VERSION 5.7 ;
  NOWIREEXTENSIONATPIN ON ;
  DIVIDERCHAR "/" ;
  BUSBITCHARS "[]" ;
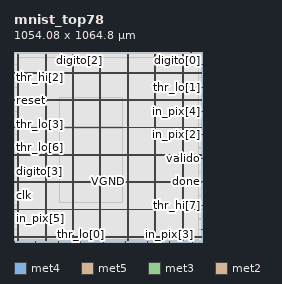
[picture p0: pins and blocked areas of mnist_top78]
MACRO mnist_top78
  CLASS BLOCK ;
  FOREIGN mnist_top78 ;
  ORIGIN 0.000 0.000 ;
  SIZE 1054.075 BY 1064.795 ;
  PIN VGND
    DIRECTION INOUT ;
    USE GROUND ;
    PORT
      LAYER met4 ;
        RECT 24.340 10.640 25.940 1052.880 ;
    END
    PORT
      LAYER met4 ;
        RECT 177.940 10.640 179.540 1052.880 ;
    END
    PORT
      LAYER met4 ;
        RECT 331.540 10.640 333.140 1052.880 ;
    END
    PORT
      LAYER met4 ;
        RECT 485.140 10.640 486.740 1052.880 ;
    END
    PORT
      LAYER met4 ;
        RECT 638.740 10.640 640.340 1052.880 ;
    END
    PORT
      LAYER met4 ;
        RECT 792.340 10.640 793.940 1052.880 ;
    END
    PORT
      LAYER met4 ;
        RECT 945.940 10.640 947.540 1052.880 ;
    END
    PORT
      LAYER met5 ;
        RECT 5.280 30.030 1048.580 31.630 ;
    END
    PORT
      LAYER met5 ;
        RECT 5.280 183.210 1048.580 184.810 ;
    END
    PORT
      LAYER met5 ;
        RECT 5.280 336.390 1048.580 337.990 ;
    END
    PORT
      LAYER met5 ;
        RECT 5.280 489.570 1048.580 491.170 ;
    END
    PORT
      LAYER met5 ;
        RECT 5.280 642.750 1048.580 644.350 ;
    END
    PORT
      LAYER met5 ;
        RECT 5.280 795.930 1048.580 797.530 ;
    END
    PORT
      LAYER met5 ;
        RECT 5.280 949.110 1048.580 950.710 ;
    END
  END VGND
  PIN VPWR
    DIRECTION INOUT ;
    USE POWER ;
    PORT
      LAYER met4 ;
        RECT 21.040 10.640 22.640 1052.880 ;
    END
    PORT
      LAYER met4 ;
        RECT 174.640 10.640 176.240 1052.880 ;
    END
    PORT
      LAYER met4 ;
        RECT 328.240 10.640 329.840 1052.880 ;
    END
    PORT
      LAYER met4 ;
        RECT 481.840 10.640 483.440 1052.880 ;
    END
    PORT
      LAYER met4 ;
        RECT 635.440 10.640 637.040 1052.880 ;
    END
    PORT
      LAYER met4 ;
        RECT 789.040 10.640 790.640 1052.880 ;
    END
    PORT
      LAYER met4 ;
        RECT 942.640 10.640 944.240 1052.880 ;
    END
    PORT
      LAYER met5 ;
        RECT 5.280 26.730 1048.580 28.330 ;
    END
    PORT
      LAYER met5 ;
        RECT 5.280 179.910 1048.580 181.510 ;
    END
    PORT
      LAYER met5 ;
        RECT 5.280 333.090 1048.580 334.690 ;
    END
    PORT
      LAYER met5 ;
        RECT 5.280 486.270 1048.580 487.870 ;
    END
    PORT
      LAYER met5 ;
        RECT 5.280 639.450 1048.580 641.050 ;
    END
    PORT
      LAYER met5 ;
        RECT 5.280 792.630 1048.580 794.230 ;
    END
    PORT
      LAYER met5 ;
        RECT 5.280 945.810 1048.580 947.410 ;
    END
  END VPWR
  PIN clk
    DIRECTION INPUT ;
    USE SIGNAL ;
    ANTENNAGATEAREA 1.721400 ;
    ANTENNADIFFAREA 0.869400 ;
    PORT
      LAYER met3 ;
        RECT 0.000 261.840 4.000 262.440 ;
    END
  END clk
  PIN digito[0]
    DIRECTION OUTPUT TRISTATE ;
    USE SIGNAL ;
    ANTENNADIFFAREA 0.795200 ;
    PORT
      LAYER met2 ;
        RECT 991.850 1060.795 992.130 1064.795 ;
    END
  END digito[0]
  PIN digito[1]
    DIRECTION OUTPUT TRISTATE ;
    USE SIGNAL ;
    ANTENNADIFFAREA 0.795200 ;
    PORT
      LAYER met2 ;
        RECT 499.190 0.000 499.470 4.000 ;
    END
  END digito[1]
  PIN digito[2]
    DIRECTION OUTPUT TRISTATE ;
    USE SIGNAL ;
    ANTENNADIFFAREA 0.795200 ;
    PORT
      LAYER met2 ;
        RECT 367.170 1060.795 367.450 1064.795 ;
    END
  END digito[2]
  PIN digito[3]
    DIRECTION OUTPUT TRISTATE ;
    USE SIGNAL ;
    ANTENNADIFFAREA 0.795200 ;
    PORT
      LAYER met3 ;
        RECT 0.000 394.440 4.000 395.040 ;
    END
  END digito[3]
  PIN done
    DIRECTION OUTPUT TRISTATE ;
    USE SIGNAL ;
    ANTENNADIFFAREA 0.795200 ;
    PORT
      LAYER met3 ;
        RECT 1050.075 336.640 1054.075 337.240 ;
    END
  END done
  PIN in_pix[0]
    DIRECTION INPUT ;
    USE SIGNAL ;
    ANTENNAGATEAREA 0.213000 ;
    PORT
      LAYER met2 ;
        RECT 618.330 1060.795 618.610 1064.795 ;
    END
  END in_pix[0]
  PIN in_pix[1]
    DIRECTION INPUT ;
    USE SIGNAL ;
    ANTENNAGATEAREA 0.495000 ;
    PORT
      LAYER met2 ;
        RECT 998.290 0.000 998.570 4.000 ;
    END
  END in_pix[1]
  PIN in_pix[2]
    DIRECTION INPUT ;
    USE SIGNAL ;
    ANTENNAGATEAREA 0.159000 ;
    PORT
      LAYER met3 ;
        RECT 1050.075 601.840 1054.075 602.440 ;
    END
  END in_pix[2]
  PIN in_pix[3]
    DIRECTION INPUT ;
    USE SIGNAL ;
    ANTENNAGATEAREA 0.247500 ;
    PORT
      LAYER met2 ;
        RECT 872.710 0.000 872.990 4.000 ;
    END
  END in_pix[3]
  PIN in_pix[4]
    DIRECTION INPUT ;
    USE SIGNAL ;
    ANTENNAGATEAREA 0.213000 ;
    PORT
      LAYER met3 ;
        RECT 1050.075 731.040 1054.075 731.640 ;
    END
  END in_pix[4]
  PIN in_pix[5]
    DIRECTION INPUT ;
    USE SIGNAL ;
    ANTENNAGATEAREA 0.852000 ;
    PORT
      LAYER met3 ;
        RECT 0.000 129.240 4.000 129.840 ;
    END
  END in_pix[5]
  PIN in_pix[6]
    DIRECTION INPUT ;
    USE SIGNAL ;
    ANTENNAGATEAREA 0.852000 ;
    PORT
      LAYER met2 ;
        RECT 0.090 0.000 0.370 4.000 ;
    END
  END in_pix[6]
  PIN in_pix[7]
    DIRECTION INPUT ;
    USE SIGNAL ;
    ANTENNAGATEAREA 0.159000 ;
    PORT
      LAYER met2 ;
        RECT 740.690 1060.795 740.970 1064.795 ;
    END
  END in_pix[7]
  PIN in_valid
    DIRECTION INPUT ;
    USE SIGNAL ;
    ANTENNAGATEAREA 0.247500 ;
    PORT
      LAYER met2 ;
        RECT 866.270 1060.795 866.550 1064.795 ;
    END
  END in_valid
  PIN reset
    DIRECTION INPUT ;
    USE SIGNAL ;
    ANTENNAGATEAREA 0.247500 ;
    PORT
      LAYER met3 ;
        RECT 0.000 792.240 4.000 792.840 ;
    END
  END reset
  PIN thr_hi[0]
    DIRECTION INPUT ;
    USE SIGNAL ;
    ANTENNAGATEAREA 0.213000 ;
    PORT
      LAYER met2 ;
        RECT 241.590 1060.795 241.870 1064.795 ;
    END
  END thr_hi[0]
  PIN thr_hi[1]
    DIRECTION INPUT ;
    USE SIGNAL ;
    ANTENNAGATEAREA 0.495000 ;
    PORT
      LAYER met2 ;
        RECT 750.350 0.000 750.630 4.000 ;
    END
  END thr_hi[1]
  PIN thr_hi[2]
    DIRECTION INPUT ;
    USE SIGNAL ;
    ANTENNAGATEAREA 0.247500 ;
    PORT
      LAYER met3 ;
        RECT 0.000 921.440 4.000 922.040 ;
    END
  END thr_hi[2]
  PIN thr_hi[3]
    DIRECTION INPUT ;
    USE SIGNAL ;
    ANTENNAGATEAREA 0.742500 ;
    PORT
      LAYER met3 ;
        RECT 1050.075 71.440 1054.075 72.040 ;
    END
  END thr_hi[3]
  PIN thr_hi[4]
    DIRECTION INPUT ;
    USE SIGNAL ;
    ANTENNAGATEAREA 0.852000 ;
    PORT
      LAYER met2 ;
        RECT 122.450 0.000 122.730 4.000 ;
    END
  END thr_hi[4]
  PIN thr_hi[5]
    DIRECTION INPUT ;
    USE SIGNAL ;
    ANTENNAGATEAREA 0.742500 ;
    PORT
      LAYER met2 ;
        RECT 248.030 0.000 248.310 4.000 ;
    END
  END thr_hi[5]
  PIN thr_hi[6]
    DIRECTION INPUT ;
    USE SIGNAL ;
    ANTENNAGATEAREA 0.247500 ;
    PORT
      LAYER met2 ;
        RECT 116.010 1060.795 116.290 1064.795 ;
    END
  END thr_hi[6]
  PIN thr_hi[7]
    DIRECTION INPUT ;
    USE SIGNAL ;
    ANTENNAGATEAREA 0.742500 ;
    PORT
      LAYER met3 ;
        RECT 1050.075 204.040 1054.075 204.640 ;
    END
  END thr_hi[7]
  PIN thr_lo[0]
    DIRECTION INPUT ;
    USE SIGNAL ;
    ANTENNAGATEAREA 0.495000 ;
    PORT
      LAYER met2 ;
        RECT 373.610 0.000 373.890 4.000 ;
    END
  END thr_lo[0]
  PIN thr_lo[1]
    DIRECTION INPUT ;
    USE SIGNAL ;
    ANTENNAGATEAREA 0.213000 ;
    PORT
      LAYER met3 ;
        RECT 1050.075 863.640 1054.075 864.240 ;
    END
  END thr_lo[1]
  PIN thr_lo[2]
    DIRECTION INPUT ;
    USE SIGNAL ;
    ANTENNAGATEAREA 0.247500 ;
    PORT
      LAYER met3 ;
        RECT 1050.075 996.240 1054.075 996.840 ;
    END
  END thr_lo[2]
  PIN thr_lo[3]
    DIRECTION INPUT ;
    USE SIGNAL ;
    ANTENNAGATEAREA 0.426000 ;
    PORT
      LAYER met3 ;
        RECT 0.000 659.640 4.000 660.240 ;
    END
  END thr_lo[3]
  PIN thr_lo[4]
    DIRECTION INPUT ;
    USE SIGNAL ;
    ANTENNAGATEAREA 0.213000 ;
    PORT
      LAYER met2 ;
        RECT 492.750 1060.795 493.030 1064.795 ;
    END
  END thr_lo[4]
  PIN thr_lo[5]
    DIRECTION INPUT ;
    USE SIGNAL ;
    ANTENNAGATEAREA 0.495000 ;
    PORT
      LAYER met2 ;
        RECT 624.770 0.000 625.050 4.000 ;
    END
  END thr_lo[5]
  PIN thr_lo[6]
    DIRECTION INPUT ;
    USE SIGNAL ;
    ANTENNAGATEAREA 0.495000 ;
    PORT
      LAYER met3 ;
        RECT 0.000 527.040 4.000 527.640 ;
    END
  END thr_lo[6]
  PIN thr_lo[7]
    DIRECTION INPUT ;
    USE SIGNAL ;
    ANTENNAGATEAREA 0.426000 ;
    PORT
      LAYER met3 ;
        RECT 0.000 1054.040 4.000 1054.640 ;
    END
  END thr_lo[7]
  PIN valido
    DIRECTION OUTPUT TRISTATE ;
    USE SIGNAL ;
    ANTENNADIFFAREA 0.445500 ;
    PORT
      LAYER met3 ;
        RECT 1050.075 469.240 1054.075 469.840 ;
    END
  END valido
  OBS
      LAYER li1 ;
        RECT 5.520 10.795 1048.340 1052.725 ;
      LAYER met1 ;
        RECT 0.070 10.640 1048.730 1052.880 ;
      LAYER met2 ;
        RECT 0.100 1060.515 115.730 1060.795 ;
        RECT 116.570 1060.515 241.310 1060.795 ;
        RECT 242.150 1060.515 366.890 1060.795 ;
        RECT 367.730 1060.515 492.470 1060.795 ;
        RECT 493.310 1060.515 618.050 1060.795 ;
        RECT 618.890 1060.515 740.410 1060.795 ;
        RECT 741.250 1060.515 865.990 1060.795 ;
        RECT 866.830 1060.515 991.570 1060.795 ;
        RECT 992.410 1060.515 1048.710 1060.795 ;
        RECT 0.100 4.280 1048.710 1060.515 ;
        RECT 0.650 3.670 122.170 4.280 ;
        RECT 123.010 3.670 247.750 4.280 ;
        RECT 248.590 3.670 373.330 4.280 ;
        RECT 374.170 3.670 498.910 4.280 ;
        RECT 499.750 3.670 624.490 4.280 ;
        RECT 625.330 3.670 750.070 4.280 ;
        RECT 750.910 3.670 872.430 4.280 ;
        RECT 873.270 3.670 998.010 4.280 ;
        RECT 998.850 3.670 1048.710 4.280 ;
      LAYER met3 ;
        RECT 4.400 1053.640 1050.075 1054.505 ;
        RECT 3.990 997.240 1050.075 1053.640 ;
        RECT 3.990 995.840 1049.675 997.240 ;
        RECT 3.990 922.440 1050.075 995.840 ;
        RECT 4.400 921.040 1050.075 922.440 ;
        RECT 3.990 864.640 1050.075 921.040 ;
        RECT 3.990 863.240 1049.675 864.640 ;
        RECT 3.990 793.240 1050.075 863.240 ;
        RECT 4.400 791.840 1050.075 793.240 ;
        RECT 3.990 732.040 1050.075 791.840 ;
        RECT 3.990 730.640 1049.675 732.040 ;
        RECT 3.990 660.640 1050.075 730.640 ;
        RECT 4.400 659.240 1050.075 660.640 ;
        RECT 3.990 602.840 1050.075 659.240 ;
        RECT 3.990 601.440 1049.675 602.840 ;
        RECT 3.990 528.040 1050.075 601.440 ;
        RECT 4.400 526.640 1050.075 528.040 ;
        RECT 3.990 470.240 1050.075 526.640 ;
        RECT 3.990 468.840 1049.675 470.240 ;
        RECT 3.990 395.440 1050.075 468.840 ;
        RECT 4.400 394.040 1050.075 395.440 ;
        RECT 3.990 337.640 1050.075 394.040 ;
        RECT 3.990 336.240 1049.675 337.640 ;
        RECT 3.990 262.840 1050.075 336.240 ;
        RECT 4.400 261.440 1050.075 262.840 ;
        RECT 3.990 205.040 1050.075 261.440 ;
        RECT 3.990 203.640 1049.675 205.040 ;
        RECT 3.990 130.240 1050.075 203.640 ;
        RECT 4.400 128.840 1050.075 130.240 ;
        RECT 3.990 72.440 1050.075 128.840 ;
        RECT 3.990 71.040 1049.675 72.440 ;
        RECT 3.990 10.715 1050.075 71.040 ;
      LAYER met4 ;
        RECT 16.855 11.735 20.640 1035.465 ;
        RECT 23.040 11.735 23.940 1035.465 ;
        RECT 26.340 11.735 174.240 1035.465 ;
        RECT 176.640 11.735 177.540 1035.465 ;
        RECT 179.940 11.735 327.840 1035.465 ;
        RECT 330.240 11.735 331.140 1035.465 ;
        RECT 333.540 11.735 481.440 1035.465 ;
        RECT 483.840 11.735 484.740 1035.465 ;
        RECT 487.140 11.735 635.040 1035.465 ;
        RECT 637.440 11.735 638.340 1035.465 ;
        RECT 640.740 11.735 788.640 1035.465 ;
        RECT 791.040 11.735 791.940 1035.465 ;
        RECT 794.340 11.735 942.240 1035.465 ;
        RECT 944.640 11.735 945.540 1035.465 ;
        RECT 947.940 11.735 1035.625 1035.465 ;
      LAYER met5 ;
        RECT 254.500 799.130 608.460 811.700 ;
        RECT 254.500 645.950 608.460 791.030 ;
        RECT 254.500 492.770 608.460 637.850 ;
        RECT 254.500 339.590 608.460 484.670 ;
        RECT 254.500 221.900 608.460 331.490 ;
  END
END mnist_top78
END LIBRARY

